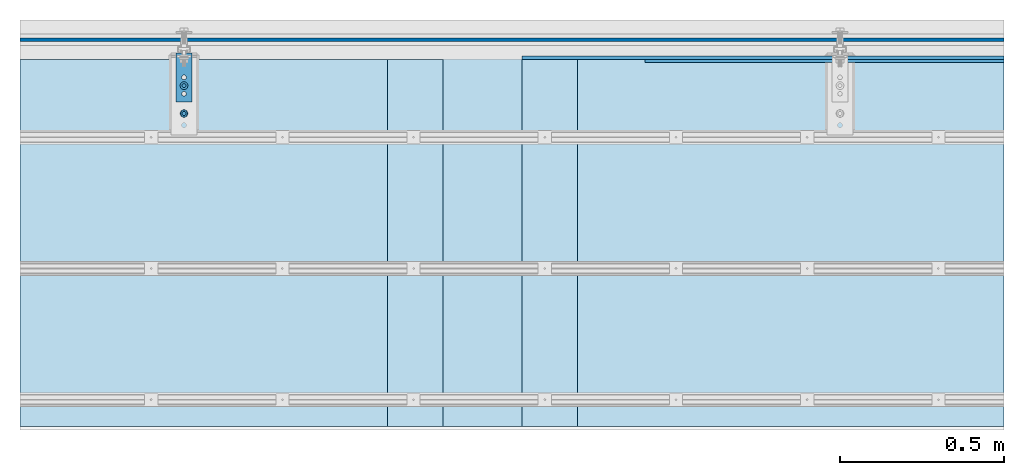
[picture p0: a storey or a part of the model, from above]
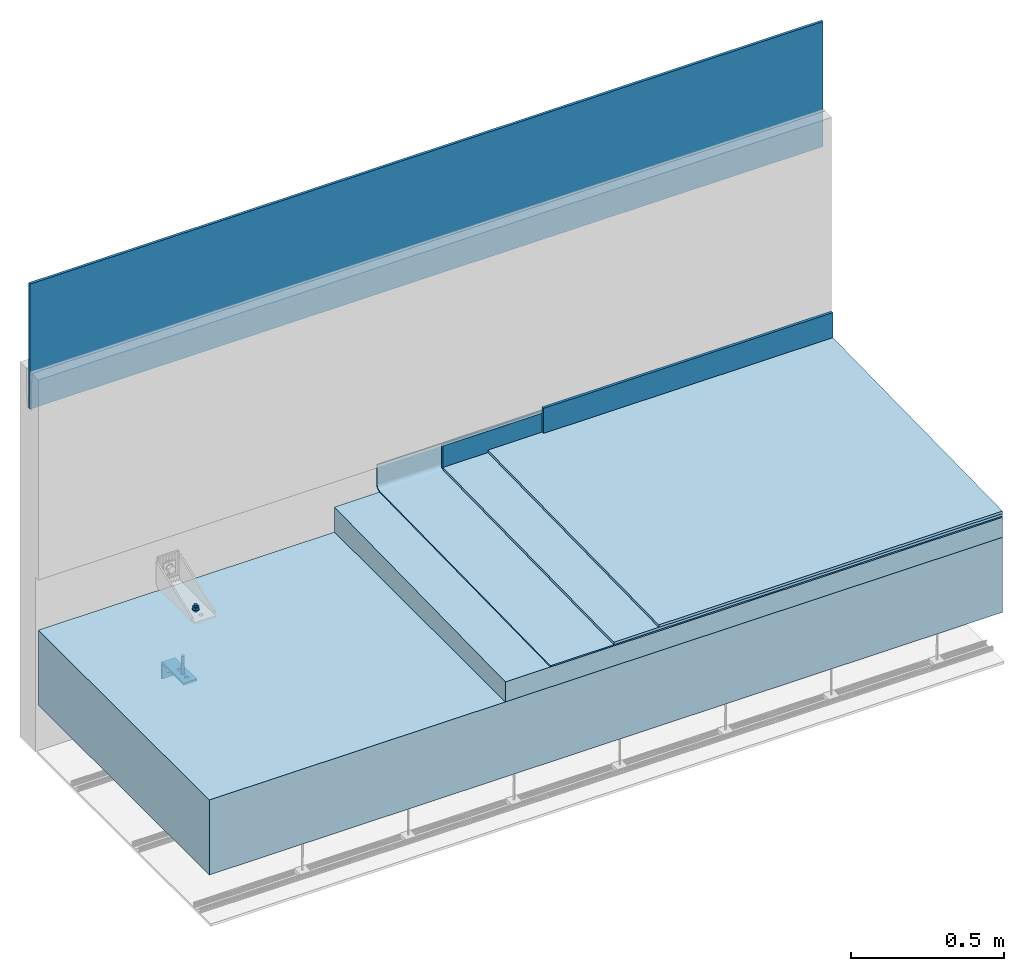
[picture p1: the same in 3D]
Properties of the parts of a building model (IFC2X3)

# File
Description: ViewDefinition [CoordinationView_V2.0, QuantityTakeOffAddOnView], RevitIdentifiers [ContentGUID: 704ee8e6-b7a5-4cdf-b516-c9cadaf13e75, VersionGUID: cb5e6814-f223-4727-abd5-230b35d57561, NumberOfSaves: 55], CoordinateReference [CoordinateBase: Shared Coordinates, ProjectSite: Internal]
File name: Solucion panel prefabricado peto.ifc
Time: 2026-03-16T13:09:40+01:00
Written by: ODA SDAI 24.6
Made in: Autodesk Revit 24.3.40.26 (ESP) - IFC 24.3.20.0

# IfcProject, 000000
LongName: Solución panel prefabricado para peto de terraza

# IfcSite, Default
RefLatitude: 40, 25, 13, 9643; RefLongitude: -3, -42, -20, -772056; RefElevation: 0 m
Otra - Categoría: Información de proyecto; Dirección de proyecto: Parque Empresarial de A Pontenova , Parcelas 33-39 , 27720 · A Pontenova · (Lugo); Fecha de emisión de proyecto: 25-11-2025; Nombre de cliente: Recense; Nombre de proyecto: Solución panel prefabricado para peto de terraza; Número de proyecto: 000000
Datos de identidad - Autor: Deliprogal; Descripción de organización: Fijaciones a medida para prefabricado; Nombre de organización: Recense

# IfcBuilding
Pset_BuildingCommon - NumberOfStoreys: 1
Otra - Categoría: Información de proyecto; Dirección de proyecto: Parque Empresarial de A Pontenova , Parcelas 33-39 , 27720 · A Pontenova · (Lugo); Fecha de emisión de proyecto: 25-11-2025; Nombre de cliente: Recense; Nombre de proyecto: Solución panel prefabricado para peto de terraza; Número de proyecto: 000000
Datos de identidad - Autor: Deliprogal; Descripción de organización: Fijaciones a medida para prefabricado; Nombre de organización: Recense

# IfcBuildingStorey: Nivel:8mm Head, L0
LongName: L0; Elevation: 0 m
Otra - Categoría: Niveles; Familia: Nivel; Familia y tipo: Nivel: 8mm Head; ID de tipo: 305; Tipo: 8mm Head
Restricciones - Elevación: 0 m
Cotas - Altura de cálculo: 0 m
Datos de identidad - Estructura: no; Nombre: L0; Planta de edificio: yes
Otra(Tipo) - Categoría: Niveles; Nombre de familia: Nivel
Restricciones(Tipo) - Base de elevación: Punto base del proyecto
Gráficos(Tipo) - Color: 12615680; Grosor de línea: 1; Patrón de línea: Dash dot; Símbolo en extremo 1 por defecto: no; Símbolo en extremo 2 por defecto: yes
Datos de identidad(Tipo) - Nombre de tipo: 8mm Head

# IfcBuildingElementProxy: Montantes falso techo:Montantes falso techo (3)
In: L0
Type - Material: REC_Acero, S 275JR (Zincado)
Type - Otra - Categoría: Modelos genéricos; Nombre de familia: Montantes falso techo
Type - Restricciones - Elevación por defecto: 13.1234 m
Type - Datos de identidad - Nombre de tipo: Montantes falso techo
Pset_BuildingElementProxyCommon - Reference: Montantes falso techo; sets with these values: 2
Otra - Familia: Montantes falso techo; Familia y tipo: Montantes falso techo: Montantes falso techo; ID de tipo: 3755326; Tipo: Montantes falso techo
Resultados de análisis - DPG_NUM_ANCL: 7
Restricciones - Desfase desde el anfitrión: 0 m; Plano de trabajo: Techo compuesto : Placa
Cotas - Área: 0.314288 m2; DPG_H_FALSO_TECHO: 0.19 m; DPG_H_Perfil: 3 m; Volumen: 0.000239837 m3
Materiales y acabados - DPG_MATERIAL: REC_Acero, S 275JR (Zincado)
Proceso por fases - Fase de creación: New
Name (Montantes falso techo:Montantes falso techo:...) | Elevación desde el nivel (m)
3755286 | -0.49 | Restricciones - Nivel: L0; Nivel de tabla de planificación: L0
3757557 | 0
3757566 | 0

# IfcBuildingElementProxy: Panel Hormigón:Panel Hormigón, Panel Hormigón:Panel Hormigón:3637775
In: L0
Type - Material: Hormigón reforzado con fibra de vidrio
Type - Otra - Categoría: Modelos genéricos; Nombre de familia: Panel Hormigón
Type - Restricciones - Elevación por defecto: 13.1234 m
Type - Datos de identidad - Nombre de tipo: Panel Hormigón
Pset_BuildingElementProxyCommon - Reference: Panel Hormigón; sets with these values: 2
Otra - Familia: Panel Hormigón; Familia y tipo: Panel Hormigón: Panel Hormigón; ID de tipo: 3674676; Tipo: Panel Hormigón
Restricciones - Desfase desde el anfitrión: -0.5 m; Elevación desde el nivel: 0 m; Plano de trabajo: <no asociado>
Cotas - Área: 5.47519 m2; Volumen: 0.483074 m3
Proceso por fases - Fase de creación: New

# IfcBuildingElementProxy: Sellado:Sellado, Sellado:Sellado:3746249
In: L0
Type - Material: Caucho, negro
Type - Otra - Categoría: Modelos genéricos; Nombre de familia: Sellado
Type - Datos de identidad - Nombre de tipo: Sellado
Pset_BuildingElementProxyCommon - Reference: Sellado; sets with these values: 2
Otra - Familia: Sellado; Familia y tipo: Sellado: Sellado; ID de tipo: 3746247; Tipo: Sellado
Restricciones - Elevación desde el nivel: 0 m; Se mueve con elementos cercanos: no
Cotas - Área: 0.00341497 m2; Volumen: 0.010245 m3
Proceso por fases - Fase de creación: New

# IfcCovering: Techo compuesto:Placa, Techo compuesto:Placa:3745222
In: L0
Type - PredefinedType: CEILING
Type - Otra - Categoría: Techos; Nombre de familia: Techo compuesto
Type - Construcción - Grosor: 0.01 m
Type - Gráficos - Color de relleno de detalle bajo: 0
Type - Datos de identidad - Nombre de tipo: Placa
Type - Propiedades analíticas - Absortancia: 0.7; Aspereza: 3; Coeficiente de transferencia de calor (U): 51 kg/K/s3; Masa térmica: 10752 kg/K/s2; Resistencia térmica (R): 0.0196078 s3*K/kg
Type - Pset_CoveringCommon - TotalThickness: 0.01 m
Material: Enlucido 0.01 m
Pset_CoveringCommon - Reference: Placa; Finish: Enlucido;
Pset_QuantityTakeOff - Reference: Placa
BaseQuantities - GrossCeilingArea: 3.42 m2
Otra - Familia: Techo compuesto; Familia y tipo: Techo compuesto: Placa; ID de tipo: 3635581; Tipo: Placa
Restricciones - Delimitación de habitación: yes; Nivel: L0; Desfase de altura desde nivel: -0.5 m
Cotas - Área: 3.42 m2; Perímetro: 8.28 m; Volumen: 0.0342 m3
Proceso por fases - Fase de creación: New

# IfcElementAssembly: GEN-A-M12:A-M12 (2)
In: L0
Type - Material: REC_Acero, S 275JR (Zincado)
Type - Otra - Categoría: Conexiones estructurales; Nombre de familia: GEN-A-M12
Type - Restricciones - Elevación por defecto: 0 m
Type - Datos - Classification.Uniclass.Pr.Description: Bolts and accessories; Classification.Uniclass.Pr.Number: Pr_20_29_08
Type - Datos de identidad - Código de montaje: Tornillo perfil hormigón M12x50 mm (8.8); Costo: 0; Creado por:: Deliprogal SL; Descripción: Arandela M12; Description_ESP: Concrete profile screw M12x50 mm (8.8); Fabricante: RECENSE; Fecha de Creacion:: 09/11/2025; Fecha Ultima Revision:: 12/02/2026; Keynote_ESP: Screw for fixing elements to the concrete profile PH4022; Modelo: TPH1250; Nombre de tipo: A-M12; Nota clave: Tornillo para fijar elementos al Perfil de Hormigón PH4022; URL: https://prefabricados.recense.com/prefabricados/fijacion/fijacion-antivuelco-hormigon/tph/
Classification: Tornillo perfil hormigón M12x50 mm (8.8) (Uniformat)
Pset_QuantityTakeOff - Reference: A-M12
Otra - Familia: GEN-A-M12; Familia y tipo: GEN-A-M12: A-M12; ID de tipo: 3651128; Tipo: A-M12
Restricciones - Se mueve con elementos cercanos: no; Anfitrión: Panel Hormigón : Panel Hormigón
Datos - DPG_FABRICA: IL; DPG_NUMERO_OT: OT-
Cotas - Área: 0.000441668 m2; Volumen: 7.16248e-07 m3
Proceso por fases - Fase de creación: New
Name (GEN-A-M12:A-M12:...)
3744003
3744030

# IfcElementAssembly: GEN-T-M12:T-M12 (2)
In: L0
Type - Material: REC_Acero, S 275JR (Zincado)
Type - Otra - Categoría: Conexiones estructurales; Nombre de familia: GEN-T-M12
Type - Restricciones - Elevación por defecto: 0 m
Type - Datos - Classification.Uniclass.Pr.Description: Bolts and accessories; Classification.Uniclass.Pr.Number: Pr_20_29_08
Type - Datos de identidad - Costo: 0; Creado por:: Deliprogal SL; Descripción: Concrete profile screw M12x50 mm (8.8); Description_ESP: Tornillo perfil hormigón M12x50 mm (8.8).; Fabricante: FERRETERÍA; Fecha de Creacion:: 01/03/2024; Fecha Ultima Revision:: 01/03/2024; Keynote_ESP: Screw for fixing elements to the concrete profile PH4022.; Modelo: TPH1250; Nombre de tipo: T-M12; Nota clave: Tornillo para fijar elementos al Perfil de Hormigón PH4022.; URL: https://prefabricados.recense.com/prefabricados/fijacion/fijacion-antivuelco-hormigon/tph/
Pset_QuantityTakeOff - Reference: T-M12
Otra - Familia: GEN-T-M12; Familia y tipo: GEN-T-M12: T-M12; ID de tipo: 3648613; Tipo: T-M12
Restricciones - Se mueve con elementos cercanos: no; Anfitrión: Panel Hormigón : Panel Hormigón
Cotas - Área: 0.000789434 m2; Volumen: 0.00000247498 m3
Proceso por fases - Fase de creación: New
Name (GEN-T-M12:T-M12:...)
3744004
3744031

# IfcElementAssembly: REC-A-M16:A-M16 (2)
In: L0
Type - Material: REC_Acero, S 275JR (Zincado)
Type - Otra - Categoría: Conexiones estructurales; Nombre de familia: REC-A-M16
Type - Restricciones - Elevación por defecto: 0 m
Type - Datos - Classification.Uniclass.Pr.Description: Bolts and accessories; Classification.Uniclass.Pr.Number: Pr_20_29_08
Type - Datos de identidad - Costo: 0; Creado por:: Deliprogal SL; Descripción: Arandela M16; Fabricante: RECENSE; Fecha de Creacion:: 01/03/2024; Fecha Ultima Revision:: 01/03/2024; Modelo: A-M16; Nombre de tipo: A-M16; URL: https://recense.com/
Pset_QuantityTakeOff - Reference: A-M16
Otra - Familia: REC-A-M16; Familia y tipo: REC-A-M16: A-M16; ID de tipo: 3814135; Tipo: A-M16
Restricciones - Se mueve con elementos cercanos: no; Anfitrión: Panel Hormigón : Panel Hormigón
Datos - DPG_FABRICA: IL; DPG_NUMERO_OT: OT-
Cotas - Área: 0.000701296 m2; Volumen: 0.00000143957 m3
Proceso por fases - Fase de creación: New
Name (REC-A-M16:A-M16:...)
3742816
3742910

# IfcElementAssembly: REC-AEM12-100:AEM12-100 (2)
In: L0
Type - Material: REC_Acero, S 275JR (Zincado)
Type - Otra - Categoría: Conexiones estructurales; Nombre de familia: REC-AEM12-100
Type - Restricciones - Elevación por defecto: 0 m
Type - Datos - Classification.Uniclass.Pr.Description: Bolts and accessories; Classification.Uniclass.Pr.Number: Pr_20_29_08
Type - Datos de identidad - Costo: 0; Creado por:: Deliprogal SL; Descripción: Anclaje M12; Fabricante: RECENSE; Fecha de Creacion:: 01/03/2024; Fecha Ultima Revision:: 16/03/2026; Modelo: AEM12-100; Nombre de tipo: AEM12-100; URL: https://recense.com/
Pset_QuantityTakeOff - Reference: AEM12-100
Otra - Familia: REC-AEM12-100; Familia y tipo: REC-AEM12-100: AEM12-100; ID de tipo: 3808015; Tipo: AEM12-100
Restricciones - Se mueve con elementos cercanos: no; Anfitrión: Panel Hormigón : Panel Hormigón
Datos - DPG_FABRICA: IL; DPG_NUMERO_OT: OT-
Cotas - Área: 0.00338965 m2; Volumen: 0.0000142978 m3
Proceso por fases - Fase de creación: New
Name (REC-AEM12-100:AEM12-100:...)
3744002
3744029

# IfcElementAssembly: REC-AEM12-140:AEM12-140 (2)
In: L0
Type - Material: REC_Acero, S 275JR (Zincado)
Type - Otra - Categoría: Conexiones estructurales; Nombre de familia: REC-AEM12-140
Type - Restricciones - Elevación por defecto: 0 m
Type - Datos - Classification.Uniclass.Pr.Description: Bolts and accessories; Classification.Uniclass.Pr.Number: Pr_20_29_08
Type - Datos de identidad - Costo: 0; Creado por:: Deliprogal SL; Descripción: Anclaje M12; Fabricante: GENERICO; Fecha de Creacion:: 07/11/2025; Fecha Ultima Revision:: 16/03/2026; Modelo: AEM12-140; Nombre de tipo: AEM12-140; URL: https://recense.com/
Pset_QuantityTakeOff - Reference: AEM12-140
Otra - Familia: REC-AEM12-140; Familia y tipo: REC-AEM12-140: AEM12-140; ID de tipo: 3808021; Tipo: AEM12-140
Restricciones - Se mueve con elementos cercanos: no; Anfitrión: Panel Hormigón : Panel Hormigón
Cotas - Área: 0.00414363 m2; Volumen: 0.0000188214 m3
Proceso por fases - Fase de creación: New
Name (REC-AEM12-140:AEM12-140:...)
3742818
3742912

# IfcElementAssembly: REC-CPA448T17:CPA448T17 (2)
In: L0
Type - Material: REC_Acero, S 275JR (Zincado)
Type - Otra - Categoría: Conexiones estructurales; Nombre de familia: REC-CPA448T17
Type - Restricciones - Elevación por defecto: 0 m
Type - Datos - Classification.Uniclass.Pr.Description: Plate (square) washers; Classification.Uniclass.Pr.Number: Pr_20_29_60_63
Type - Datos de identidad - Costo: 0; Creado por:: Deliprogal SL; Descripción: Contraplaca antideslizante; Fabricante: RECENSE; Fecha de Creacion:: 10/11/2025; Fecha Ultima Revision:: 16/03/2026; Modelo: CPA448T17; Nombre de tipo: CPA448T17; URL: https://prefabricados.recense.com/prefabricados/fijacion/fijacion-antivuelco-hormigon/para2501208rt/
Pset_QuantityTakeOff - Reference: CPA448T17
Otra - Familia: REC-CPA448T17; Familia y tipo: REC-CPA448T17: CPA448T17; ID de tipo: 3606529; Tipo: CPA448T17
Restricciones - Se mueve con elementos cercanos: no; Anfitrión: Ninguno
Datos - DPG_FABRICA: IL; DPG_NUMERO_OT: OT-
Cotas - Área: 0.00433573 m2; Volumen: 0.0000136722 m3
Proceso por fases - Fase de creación: New
Name (REC-CPA448T17:CPA448T17:...)
3814303
3814305

# IfcElementAssembly: REC-HBP M16-75 EV:HBP M16-75 EV (2)
In: L0
Type - Material: REC_Acero, S 275JR (Zincado)
Type - Otra - Categoría: Conexiones estructurales; Nombre de familia: REC-HBP M16-75 EV
Type - Restricciones - Elevación por defecto: 0 m
Type - Datos - Classification.Uniclass.Pr.Description: Lifting anchors; Classification.Uniclass.Pr.Number: Pr_20_29_03_47
Type - Datos de identidad - Costo: 0; Creado por:: Deliprogal SL; Descripción: Casquillo fijación HBP; Description_ESP: CASQUILLO; Fabricante: RECENSE; Fecha de Creacion:: 07/11/2025; Fecha Ultima Revision:: 06/02/2026; Keynote_ESP: Casquillo e insertos roscados hembra para dejar embebidos en los prefabricados de hormigón y ser usados posteriormente para su fijación a la estructura del edificio, o para la instalación de elementos auxiliares.; Modelo: HBP M16x75 EV; Nombre de tipo: HBP M16-75 EV; Nota clave: Female threaded sleeves and inserts designed to be embedded in precast concrete elements and later used for fastening them to the building structure or for installing auxiliary components.; URL: https://prefabricados.recense.com/prefabricados/fijacion/casquillos-estandar/
Pset_QuantityTakeOff - Reference: HBP M16-75 EV
Otra - Familia: REC-HBP M16-75 EV; Familia y tipo: REC-HBP M16-75 EV: HBP M16-75 EV; ID de tipo: 3606532; Tipo: HBP M16-75 EV
Restricciones - Anfitrión: Panel Hormigón : Panel Hormigón; Se mueve con elementos cercanos: no
Cotas - Área: 0.00790422 m2; Volumen: 0.0000329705 m3
Proceso por fases - Fase de creación: New
Estructura - Recubrimiento de armadura: Rebar Cover 1 <25 mm>
Name (REC-HBP M16-75 EV:HBP M16-75 EV:...)
3742815
3742909

# IfcElementAssembly: REC-M16-45:M16-45 (2)
In: L0
Type - Material: REC_Acero, S 275JR (Zincado)
Type - Otra - Categoría: Conexiones estructurales; Nombre de familia: REC-M16-45
Type - Restricciones - Elevación por defecto: 0 m
Type - Datos - Classification.Uniclass.Pr.Description: Bolts and accessories; Classification.Uniclass.Pr.Number: Pr_20_29_08
Type - Datos de identidad - Costo: 0; Creado por:: Deliprogal SL; Descripción: Tornillo M16 L=45; Fabricante: RECENSE; Fecha de Creacion:: 01/03/2024; Fecha Ultima Revision:: 01/03/2024; Modelo: M16-45; Nombre de tipo: M16-45; URL: https://recense.com/
Pset_QuantityTakeOff - Reference: M16-45
Otra - Familia: REC-M16-45; Familia y tipo: REC-M16-45: M16-45; ID de tipo: 3814134; Tipo: M16-45
Restricciones - Se mueve con elementos cercanos: no; Anfitrión: Panel Hormigón : Panel Hormigón
Datos - DPG_FABRICA: IL; DPG_NUMERO_OT: OT-
Cotas - Área: 0.00240261 m2; Volumen: 0.0000157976 m3
Proceso por fases - Fase de creación: New
Name (REC-M16-45:M16-45:...)
3742817
3742911

# IfcElementAssembly: REC-PAA150708T14:PAA150708T14 (2)
In: L0
Type - Material: REC_Acero, S 275JR (Zincado)
Type - Otra - Categoría: Conexiones estructurales; Nombre de familia: REC-PAA150708T14
Type - Restricciones - Elevación por defecto: 0 m
Type - Datos - Classification.Uniclass.Pr.Description: Carbon steel anchor plates; Classification.Uniclass.Pr.Number: Pr_20_29_03_10
Type - Datos de identidad - Costo: 0; Creado por:: Deliprogal SL; Descripción: Non-slip angle plate 150x70x50x8, with 3 holes Ø14 mm on one side and hole Ø14 mm on another side.; Description_ESP: Pletina angular antideslizante 150x70x50x8 mm, 3 taladros TØ14 mm en un ala y TØ14 mm en la otra.; Fabricante: RECENSE; Fecha de Creacion:: 01/11/2025; Fecha Ultima Revision:: 06/02/2025; Keynote_ESP: Anclaje antivuelco para fijación de paneles a estructura de hormigón mediante la interposición de perfiles y/ó tornillos de anclaje expansivo.; Modelo: PAA150708T14; Nombre de tipo: PAA150708T14; Nota clave: Anti-tilt anchor for fixing panels to concrete structures by means of interposing profiles and/or expansion anchor bolts.; URL: https://prefabricados.recense.com/prefabricados/fijacion/fijacion-antivuelco-hormigon/paaxxx708t14/
Type - Visibilidad - Visible: yes
Pset_QuantityTakeOff - Reference: PAA150708T14
Otra - Familia: REC-PAA150708T14; Familia y tipo: REC-PAA150708T14: PAA150708T14; ID de tipo: 3770379; Tipo: PAA150708T14
Restricciones - Se mueve con elementos cercanos: no; Anfitrión: Ninguno
Cotas - Área: 0.0125823 m2; Volumen: 0.0000784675 m3
Proceso por fases - Fase de creación: New
Name (REC-PAA150708T14:PAA150708T14:...)
3770603
3770604

# IfcElementAssembly: REC-PARA2501208RT:PARA2501208RT (2)
In: L0
Type - Material: REC_Acero, S 275JR (Zincado)
Type - Otra - Categoría: Conexiones estructurales; Nombre de familia: REC-PARA2501208RT
Type - Restricciones - Elevación por defecto: 0 m
Type - Datos - Classification.Uniclass.Pr.Description: Brackets; Classification.Uniclass.Pr.Number: Pr_20_85_09
Type - Datos de identidad - Costo: 0; Creado por:: Deliprogal SL; Descripción: Pletina reforzada PARA; Fabricante: RECENSE; Fecha de Creacion:: 8/11/2025; Fecha Ultima Revision:: 16/03/2026; Modelo: PARA2501208RT; Nombre de tipo: PARA2501208RT; URL: https://prefabricados.recense.com/prefabricados/fijacion/fijacion-antivuelco-hormigon/para2501208rt/
Pset_QuantityTakeOff - Reference: PARA2501208RT
Otra - Familia: REC-PARA2501208RT; Familia y tipo: REC-PARA2501208RT: PARA2501208RT; ID de tipo: 3606530; Tipo: PARA2501208RT
Restricciones - Se mueve con elementos cercanos: no; Anfitrión: Ninguno
Cotas - Área: 0.0616333 m2; Volumen: 0.000369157 m3
Proceso por fases - Fase de creación: New
Name (REC-PARA2501208RT:PARA2501208RT:...)
3820377
3820378

# IfcElementAssembly: REC-PH4022:PH4022 (2)
In: L0
Type - Material: REC_Acero, S 275JR (Zincado)
Type - Otra - Categoría: Conexiones estructurales; Nombre de familia: REC-PH4022
Type - Restricciones - Elevación por defecto: 0 m
Type - Datos - Classification.Uniclass.Pr.Description: Carbon steel cast-in channels; Classification.Uniclass.Pr.Number: Pr_20_85_84_11
Type - Datos de identidad - Costo: 0; Creado por:: Deliprogal SL; Descripción: Concrete profile 150x67x40x22x22x2.5 mm.; Description_ESP: Perfil hormigón 150x67x40x22x2.5 mm.; Fabricante: RECENSE; Fecha de Creacion:: 10/11/2025; Fecha Ultima Revision:: 06/02/2026; Keynote_ESP: Perfil para dejar embebido en elementos de hormigón para su posterior fijación mediante Tornillos de Perfil de Hormigón TPH y el anclaje correspondiente.; Modelo: PH4022; Nombre de tipo: PH4022; Nota clave: Profile to be embedded in concrete elements for subsequent fixing by means of TPH Concrete Profile Screws and the corresponding anchorage.; URL: https://prefabricados.recense.com/prefabricados/fijacion/fijacion-antivuelco-hormigon/ph4022/
Pset_QuantityTakeOff - Reference: PH4022
Otra - Familia: REC-PH4022; Familia y tipo: REC-PH4022: PH4022; ID de tipo: 3770382; Tipo: PH4022
Restricciones - Se mueve con elementos cercanos: no; Anfitrión: Panel Hormigón : Panel Hormigón
Cotas - Área: 0.016689 m2; Volumen: 0.0000420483 m3
Proceso por fases - Fase de creación: New
Name (REC-PH4022:PH4022:...)
3744000
3744027

# IfcElementAssembly: REC-TPH1250:TPH1250 (2)
In: L0
Type - Material: REC_Acero, S 275JR (Zincado)
Type - Otra - Categoría: Conexiones estructurales; Nombre de familia: REC-TPH1250
Type - Restricciones - Elevación por defecto: 0 m
Type - Datos - Classification.Uniclass.Pr.Description: Bolts and accessories; Classification.Uniclass.Pr.Number: Pr_20_29_08
Type - Datos de identidad - Costo: 0; Creado por:: Deliprogal SL; Descripción: Concrete profile screw M12x50 mm (8.8); Description_ESP: Tornillo perfil hormigón M12x50 mm (8.8).; Fabricante: RECENSE; Fecha de Creacion:: 9/11/2025; Fecha Ultima Revision:: 06/02/2026; Keynote_ESP: Tornillo para fijar elementos al Perfil de Hormigón PH4022.; Modelo: TPH1250; Nombre de tipo: TPH1250; Nota clave: Screw for fixing elements to the concrete profile PH4022.; URL: https://prefabricados.recense.com/prefabricados/fijacion/fijacion-antivuelco-hormigon/tph/
Pset_QuantityTakeOff - Reference: TPH1250
Otra - Familia: REC-TPH1250; Familia y tipo: REC-TPH1250: TPH1250; ID de tipo: 3566361; Tipo: TPH1250
Restricciones - Se mueve con elementos cercanos: no; Anfitrión: Panel Hormigón : Panel Hormigón
Cotas - Área: 0.00199136 m2; DPG_PosicionTuerca: 0.015 m; Volumen: 0.00000937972 m3
Proceso por fases - Fase de creación: New
Name (REC-TPH1250:TPH1250:...)
3744001
3744028

# IfcOpeningElement: Opening (8)
In: L0
BaseQuantities - Depth: 0.05 m; Area: 0.00166786 m2
Pset_OpeningElementCommon - Reference: PAA150708T14; sets with these values: 2
Name (REC-PAA150708T14:PAA150708T14:...)
3770603:1
3770603:2
3770603:3
3770603:4
3770604:1
3770604:2
3770604:3
3770604:4

# IfcSlab: Lamina impermeable:Lamina impermeable, Lamina impermeable:Lamina impermeable:3743695
In: L0
Type - PredefinedType: FLOOR; Material: Caucho, negro
Type - Otra - Categoría: Suelos; Nombre de familia: Lamina impermeable
Type - Datos de identidad - Nombre de tipo: Lamina impermeable
Pset_QuantityTakeOff - Reference: Lamina impermeable; sets with these values: 2
Pset_SlabCommon - IsExternal: no; Reference: Lamina impermeable
BaseQuantities - Perimeter: 2.46533 m; GrossArea: 0.0061383 m2; NetArea: 0.00613831 m2; GrossVolume: 0.0104957 m3; NetVolume: 0.0104957 m3
Otra - Familia: Lamina impermeable; Familia y tipo: Lamina impermeable: Lamina impermeable; ID de tipo: 3743693; Tipo: Lamina impermeable
Restricciones - Delimitación de habitación: yes; Nivel: L0; Elevación desde el nivel: 0 m; Se mueve con elementos cercanos: no
Cotas - Área: 0.00613831 m2; Volumen: 0.0104957 m3
Proceso por fases - Fase de creación: New
Estructura - Recubrimiento de armadura: Rebar Cover 1 <25 mm>

# IfcSlab: Suelo:DPG_Ceramica, Suelo:DPG_Ceramica:3743870
In: L0
Type - PredefinedType: FLOOR; Material: Azulejo, porcelana, 6 pulg. 0.01 m
Type - Otra - Categoría: Suelos; Nombre de familia: Suelo
Type - Construcción - Función: Interior; Grosor predeterminado: 0.01 m
Type - Gráficos - Color de relleno de detalle bajo: 0
Type - Datos de identidad - Nombre de tipo: DPG_Ceramica
Type - Materiales y acabados - Material estructural: Azulejo, porcelana, 6 pulg.
Type - Propiedades analíticas - Absortancia: 0.7; Aspereza: 3; Coeficiente de transferencia de calor (U): 120 kg/K/s3; Masa térmica: 17000 kg/K/s2; Resistencia térmica (R): 0.00833333 s3*K/kg
Type - Pset_SlabCommon - ThermalTransmittance: 120 kg/K/s3
Pset_QuantityTakeOff - Reference: DPG_Ceramica; sets with these values: 2
Pset_SlabCommon - IsExternal: no; LoadBearing: no; Reference: DPG_Ceramica; PitchAngle: 1.02304 deg
BaseQuantities - Width: 1.3 m; Perimeter: 4.84036 m; GrossArea: 1.45623 m2; NetArea: 1.45623 m2; GrossVolume: 0.0145623 m3; NetVolume: 0.01456 m3
Otra - Familia: Suelo; Familia y tipo: Suelo: DPG_Ceramica; ID de tipo: 3607552; Tipo: DPG_Ceramica
Restricciones - Delimitación de habitación: yes; Nivel: L0; Relacionado con masa: no; Desfase de altura desde nivel: 0.125 m
Cotas - Área: 1.45623 m2; Grosor: 0.01 m; Perímetro: 4.84 m; Volumen: 0.0145623 m3
Datos de identidad - Tiene asociación: no
Proceso por fases - Fase de creación: New
Edición de forma de losa - Condición de borde curvado: 0
Estructura - Estructura: no

# IfcSlab: Suelo:DPG_Losa Principal Obra, Suelo:DPG_Losa Principal Obra:3592091
In: L0
Type - PredefinedType: FLOOR; Material: DPG_Losa Principal Obra 0.3 m
Type - Otra - Categoría: Suelos; Nombre de familia: Suelo
Type - Construcción - Función: Interior; Grosor predeterminado: 0.3 m
Type - Gráficos - Color de relleno de detalle bajo: 0
Type - Datos de identidad - Nombre de tipo: DPG_Losa Principal Obra
Type - Materiales y acabados - Material estructural: DPG_Losa Principal Obra
Type - Propiedades analíticas - Absortancia: 0.7; Aspereza: 3
Pset_QuantityTakeOff - Reference: DPG_Losa Principal Obra; sets with these values: 2
Pset_SlabCommon - Reference: DPG_Losa Principal Obra; IsExternal: no; LoadBearing: no; PitchAngle: 0 deg
BaseQuantities - Width: 3 m; Perimeter: 8.24 m; GrossArea: 3.36 m2; NetArea: 3.36 m2; GrossVolume: 1.008 m3; NetVolume: 1.008 m3
Otra - Familia: Suelo; Familia y tipo: Suelo: DPG_Losa Principal Obra; ID de tipo: 759; Tipo: DPG_Losa Principal Obra
Restricciones - Delimitación de habitación: yes; Desfase de altura desde nivel: 0 m; Nivel: L0; Relacionado con masa: no
Cotas - Área: 3.36 m2; Elevación en parte inferior: -0.3 m; Elevación en parte inferior de núcleo: -0.3 m; Elevación en parte superior: 0 m; Elevación en parte superior de núcleo: 0 m; Grosor: 0.3 m; Perímetro: 8.24 m; Volumen: 1.008 m3
Datos de identidad - Tiene asociación: no
Proceso por fases - Fase de creación: New
Estructura - Estructura: no

# IfcSlab: Suelo:DPG_Pegamento cemento, Suelo:DPG_Pegamento cemento:3743797
In: L0
Type - PredefinedType: FLOOR; Material: Hormigón - Hormigón moldeado in situ 0.01 m
Type - Otra - Categoría: Suelos; Nombre de familia: Suelo
Type - Construcción - Función: Interior; Grosor predeterminado: 0.01 m
Type - Gráficos - Color de relleno de detalle bajo: 0
Type - Datos de identidad - Nombre de tipo: DPG_Pegamento cemento
Type - Materiales y acabados - Material estructural: Hormigón - Hormigón moldeado in situ
Type - Propiedades analíticas - Absortancia: 0.7; Aspereza: 3
Pset_QuantityTakeOff - Reference: DPG_Pegamento cemento; sets with these values: 2
Pset_SlabCommon - IsExternal: no; LoadBearing: no; Reference: DPG_Pegamento cemento; PitchAngle: 1.02304 deg
BaseQuantities - Width: 1.47 m; Perimeter: 5.18036 m; GrossArea: 1.64666 m2; NetArea: 1.64666 m2; GrossVolume: 0.0164666 m3; NetVolume: 0.016464 m3
Otra - Familia: Suelo; Familia y tipo: Suelo: DPG_Pegamento cemento; ID de tipo: 3607442; Tipo: DPG_Pegamento cemento
Restricciones - Delimitación de habitación: yes; Nivel: L0; Relacionado con masa: no; Desfase de altura desde nivel: 0.115 m
Cotas - Área: 1.64666 m2; Grosor: 0.01 m; Perímetro: 5.18 m; Volumen: 0.0164666 m3
Datos de identidad - Tiene asociación: no
Proceso por fases - Fase de creación: New
Edición de forma de losa - Condición de borde curvado: 0
Estructura - Estructura: no

# IfcSlab: Suelo:DPG_Recrecido, Suelo:DPG_Recrecido:3607293
In: L0
Type - PredefinedType: FLOOR; Material: Hormigón, ligero 0.1 m
Type - Otra - Categoría: Suelos; Nombre de familia: Suelo
Type - Construcción - Función: Interior; Grosor predeterminado: 0.1 m
Type - Gráficos - Color de relleno de detalle bajo: 0
Type - Datos de identidad - Nombre de tipo: DPG_Recrecido
Type - Materiales y acabados - Material estructural: Hormigón, ligero
Type - Propiedades analíticas - Absortancia: 0.7; Aspereza: 3; Coeficiente de transferencia de calor (U): 2.09 kg/K/s3; Masa térmica: 62415 kg/K/s2; Resistencia térmica (R): 0.478469 s3*K/kg
Type - Pset_SlabCommon - ThermalTransmittance: 2.09 kg/K/s3
Pset_QuantityTakeOff - Reference: DPG_Recrecido; sets with these values: 2
Pset_SlabCommon - IsExternal: no; LoadBearing: no; Reference: DPG_Recrecido; PitchAngle: 1.02303 deg
BaseQuantities - Perimeter: 2.42018 m; GrossArea: 0.1008 m2; NetArea: 2.10594 m2; GrossVolume: 0.189504 m3; NetVolume: 0.189504 m3
Otra - Familia: Suelo; Familia y tipo: Suelo: DPG_Recrecido; ID de tipo: 3607308; Tipo: DPG_Recrecido
Restricciones - Delimitación de habitación: yes; Nivel: L0; Relacionado con masa: no; Desfase de altura desde nivel: 0.1 m
Cotas - Área: 2.10594 m2; Elevación en parte inferior: 0 m; Elevación en parte inferior de núcleo: 0 m; Perímetro: 6 m; Volumen: 0.189504 m3
Datos de identidad - Tiene asociación: no
Proceso por fases - Fase de creación: New
Edición de forma de losa - Condición de borde curvado: 0
Estructura - Estructura: no

# IfcWallStandardCase: Muro básico:DPG_Pegamento cementoso, Muro básico:DPG_Pegamento cementoso:3744789
In: L0
Type - PredefinedType: STANDARD; Material: Hormigón - Hormigón moldeado in situ 0.01 m
Type - Otra - Categoría: Muros; Nombre de familia: Muro básico
Type - Construcción - Anchura: 0.01 m; Envolvente en extremos: Ninguno; Envolvente en inserciones: Sin envolvente; Función: Retención
Type - Gráficos - Color de relleno de detalle bajo: 0
Type - Datos de identidad - Nombre de tipo: DPG_Pegamento cementoso
Type - Propiedades analíticas - Absortancia: 0.7; Aspereza: 3
BaseQuantities - Height: 0.0912673 m; Length: 1.47 m; Width: 0.01 m; GrossFootprintArea: 0.0147 m2; GrossVolume: 0.00134163 m3; GrossSideArea: 0.134163 m2; NetSideArea: 0.134163 m2; NetVolume: 0.00134163 m3
Pset_QuantityTakeOff - Reference: DPG_Pegamento cementoso; sets with these values: 2
Pset_WallCommon - LoadBearing: no; Reference: DPG_Pegamento cementoso; IsExternal: yes; ExtendToStructure: no
Otra - Familia: Muro básico; Familia y tipo: Muro básico: DPG_Pegamento cementoso; ID de tipo: 3744902; Tipo: DPG_Pegamento cementoso
Restricciones - Relacionado con masa: no; Altura desconectada: 0.0912673 m; Delimitación de habitación: no; Desfase de base: 0.108733 m; Desfase superior: 0 m; Distancia de extensión de base: 0 m; Distancia de extensión superior: 0 m; La base está enlazada: no; La parte superior está enlazada: no; Línea de ubicación: Cara de acabado: Exterior; Restricción de base: L0
Cotas - Área: 0.134163 m2; Longitud: 1.47 m; Volumen: 0.00134163 m3
Proceso por fases - Fase de creación: New
Estructura - Estructura: no; Uso estructural: No portante
Definición de sección transversal - Sección transversal: Vertical

# IfcWallStandardCase: Muro básico:DPG_Rodapie, Muro básico:DPG_Rodapie:3770921
In: L0
Type - PredefinedType: STANDARD; Material: Azulejo, porcelana, 6 pulg. 0.01 m
Type - Otra - Categoría: Muros; Nombre de familia: Muro básico
Type - Construcción - Envolvente en extremos: Ninguno; Envolvente en inserciones: Sin envolvente; Función: Retención; Anchura: 0.01 m
Type - Gráficos - Color de relleno de detalle bajo: 0
Type - Datos de identidad - Nombre de tipo: DPG_Rodapie
Type - Propiedades analíticas - Absortancia: 0.7; Aspereza: 3; Coeficiente de transferencia de calor (U): 120 kg/K/s3; Masa térmica: 17000 kg/K/s2; Resistencia térmica (R): 0.00833333 s3*K/kg
Type - Pset_WallCommon - ThermalTransmittance: 120 kg/K/s3
BaseQuantities - Height: 0.1 m; Length: 1.095 m; Width: 0.01 m; GrossFootprintArea: 0.01095 m2; GrossVolume: 0.001095 m3; GrossSideArea: 0.1095 m2; NetSideArea: 0.1095 m2; NetVolume: 0.001095 m3
Pset_QuantityTakeOff - Reference: DPG_Rodapie; sets with these values: 2
Pset_WallCommon - LoadBearing: no; IsExternal: yes; ExtendToStructure: no; Reference: DPG_Rodapie
Otra - Familia: Muro básico; Familia y tipo: Muro básico: DPG_Rodapie; ID de tipo: 3744321; Tipo: DPG_Rodapie
Restricciones - Relacionado con masa: no; Delimitación de habitación: no; Desfase superior: 0 m; Distancia de extensión de base: 0 m; Distancia de extensión superior: 0 m; La base está enlazada: no; La parte superior está enlazada: no; Línea de ubicación: Cara de acabado: Exterior; Restricción de base: L0; Altura desconectada: 0.1 m; Desfase de base: 0.125654 m
Cotas - Área: 0.1095 m2; Longitud: 1.095 m; Volumen: 0.001095 m3
Proceso por fases - Fase de creación: New
Estructura - Estructura: no; Uso estructural: No portante
Definición de sección transversal - Sección transversal: Vertical

# IfcWallStandardCase: Muro básico:DPG_Vidrio, Muro básico:DPG_Vidrio:3745418
In: L0
Type - PredefinedType: STANDARD; Material: Vidrio 0.01 m
Type - Otra - Categoría: Muros; Nombre de familia: Muro básico
Type - Construcción - Envolvente en extremos: Ninguno; Envolvente en inserciones: Sin envolvente; Función: Retención; Anchura: 0.01 m
Type - Gráficos - Color de relleno de detalle bajo: 0
Type - Datos de identidad - Nombre de tipo: DPG_Vidrio
Type - Propiedades analíticas - Absortancia: 0.7; Aspereza: 3
BaseQuantities - Height: 0.5 m; Length: 3 m; Width: 0.01 m; GrossFootprintArea: 0.03 m2; GrossVolume: 0.015 m3; GrossSideArea: 1.5 m2; NetSideArea: 1.5 m2; NetVolume: 0.015 m3
Pset_QuantityTakeOff - Reference: DPG_Vidrio; sets with these values: 2
Pset_WallCommon - LoadBearing: no; IsExternal: yes; ExtendToStructure: no; Reference: DPG_Vidrio
Otra - Familia: Muro básico; Familia y tipo: Muro básico: DPG_Vidrio; ID de tipo: 3745321; Tipo: DPG_Vidrio
Restricciones - Relacionado con masa: no; Delimitación de habitación: no; Desfase superior: 0 m; Distancia de extensión de base: 0 m; Distancia de extensión superior: 0 m; La base está enlazada: no; La parte superior está enlazada: no; Restricción de base: L0; Altura desconectada: 0.5 m; Desfase de base: 0.85 m; Línea de ubicación: Eje del muro
Cotas - Área: 1.5 m2; Longitud: 3 m; Volumen: 0.015 m3
Proceso por fases - Fase de creación: New
Estructura - Estructura: no; Uso estructural: No portante
Definición de sección transversal - Sección transversal: Vertical
